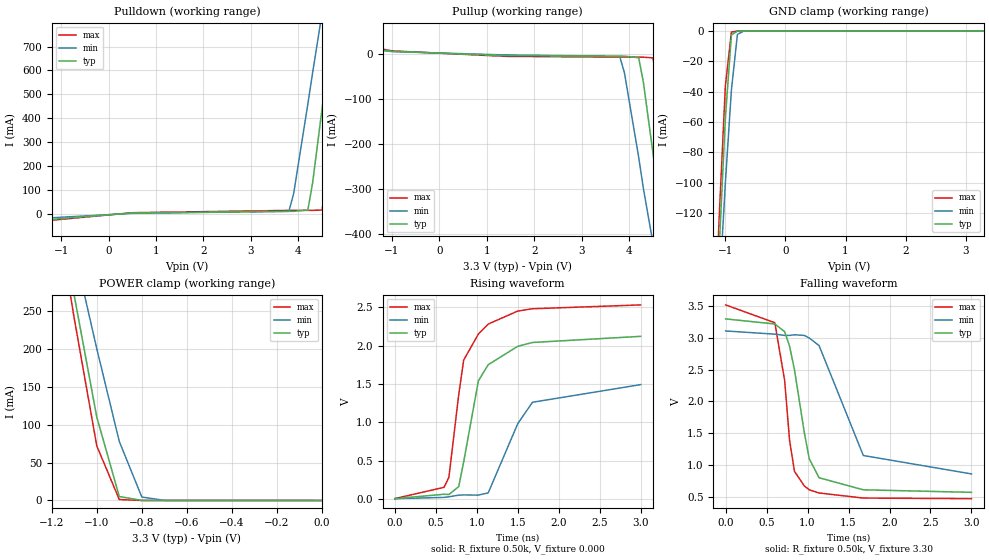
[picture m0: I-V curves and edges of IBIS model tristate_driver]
| IBIS file tristate.ibs created by s2ibis2 version 1.1
| North Carolina State University Electronics Research Laboratory  1995
[IBIS ver]   2.1
[File name]   tristate.ibs
[File Rev]   0
[Date]   April 1, 2001
[Source]   From MegaFLOPS Inc. layout and silicon models.
[Notes]   I really wouldn't try to use this driver. It's really bad.
[Disclaimer]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
[Copyright]   Copyright 2001 MegaFLOPS Inc.
|   Component MCM Trisate Driver
[Component]   MCM Trisate Driver
[Manufacturer]   MegaFLOPS Inc.
[Package]
| variable   typ   min   max
R_pkg   2.00m   1.00m   4.00m
L_pkg   0.20nH   0.10nH   0.40nH
C_pkg   2.00pF   1.00pF   4.00pF
[Pin]  signal_name   model_name   R_pin   L_pin   C_pin
out   out   tristate_driver
| in   in   dummy
| ena  enable   dummy
gnd   gnd   GND
vdd   vdd   POWER
| Models and submodels in the file (1): tristate_driver (3-state)
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|   Model tristate_driver
[Model]   tristate_driver
Model_type   3-state
Polarity   Non-Inverting
Enable   Active-Low
C_comp   5.00pF   5.00pF   5.00pF
[Temperature Range]   27.00   100.00   0.000
[Voltage Range]   3.30V   3.00V   3.60V
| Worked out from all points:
|   slope of the pulldown table from 0 to 0.495 V, typ, clamps not added: 102 ohm
|   slope of the pullup table from 0 to 0.495 V, typ, clamps not added: 229 ohm
|   GND clamp passes 1 mA (typ) near -0.84 V on its own axis
|   POWER clamp passes 1 mA (typ) near -0.82 V on its own axis
|   rising waveform, R_fixture 0.50k, V_fixture 0.000: 20-80 % time 274ps typ, 377ps min, 248ps max; typ from 0.003 V to 2.12 V
|   falling waveform, R_fixture 0.50k, V_fixture 3.30: 20-80 % time 219ps typ, 380ps min, 161ps max; typ from 3.3 V to 0.57 V
[Pulldown]
| voltage   I(typ)   I(min)   I(max)
-3.3V     -51.73mA   -3.31mA    -61.85mA
-2.7V     -45.32mA   -31.67mA   -53.63mA
500mV     4.89mA     3.3mA      5.97mA
3.8V      11.72mA    11.67mA    15.66mA
3.9V      11.73mA    84.95mA    15.68mA
4.2V      17.13mA    460mA      15.72mA
4.3V      130mA      590mA      15.74mA
4.5V      440mA      840mA      17.16mA
4.7V      750mA      1.09A      260mA
4.9V      1.07A      1.35A      610mA
5.1V      1.38A      1.6A       950mA
6.6V      3.74A      3.5A       3.54A
[Pullup]
| voltage   I(typ)   I(min)   I(max)
-3.3V     44.21mA    32.14mA    52.15mA
-1V       5.21mA     4.54mA     6.16mA
1.4V      -4.72mA    -2.92mA    -6.11mA
3.8V      -5.59mA    -5.85mA    -7.73mA
3.9V      -5.62mA    -42.88mA   -7.74mA
4.2V      -9.1mA     -230mA     -7.79mA
4.3V      -64.3mA    -300mA     -7.93mA
4.5V      -220mA     -420mA     -9.41mA
4.7V      -380mA     -550mA     -130mA
4.9V      -540mA     -680mA     -310mA
5.1V      -700mA     -810mA     -480mA
6.6V      -1.89A     -1.77A     -1.79A
[GND_clamp]
| voltage   I(typ)   I(min)   I(max)
-3.3V     -1.88A     -1.57A     -2.04A
-1.2V     -210mA     -230mA     -210mA
-1.1V     -140mA     -170mA     -120mA
-1V       -57.32mA   -100mA     -36.14mA
-900mV    -2.63mA    -39mA      -630uA
-800mV    -55.14uA   -2.27mA    -9.15uA
-700mV    -1.16uA    -100uA     -140nA
3.3V      2.75pA     810pA      2.5pA
[POWER_clamp]
| voltage   I(typ)   I(min)   I(max)
-3.3V     3.73A      3.11A      4.05A
-1.2V     430mA      460mA      420mA
-1.1V     270mA      330mA      240mA
-1V       110mA      200mA      71.98mA
-900mV    5.24mA     77.73mA    1.26mA
-800mV    110uA      4.53mA     17.99uA
-700mV    2.3uA      200uA      260nA
0V        2.75pA     2.68pA     3pA
[Ramp]
| variable   typ   min   max
dV/dt_r   1.27/0.29n   0.89/0.37n   1.52/0.25n
dV/dt_f   1.64/0.20n   1.34/0.33n   1.85/0.16n
R_load = 0.50k
[Rising Waveform]
R_fixture = 0.50k
V_fixture = 0.000
| time   V(typ)   V(min)   V(max)
0s        2.53mV     1.85mV     3.15mV
600ps     59.63mV    18.84mV    150mV
660ps     56.14mV    26.37mV    280mV
780ps     160mV      48.29mV    1.36V
840ps     480mV      50.62mV    1.81V
1.02ns    1.54V      49.2mV     2.15V
1.14ns    1.75V      77.56mV    2.28V
1.5ns     1.99V      980mV      2.45V
1.68ns    2.04V      1.26V      2.48V
3ns       2.12V      1.49V      2.53V
[Falling Waveform]
R_fixture = 0.50k
V_fixture = 3.30
| time   V(typ)   V(min)   V(max)
0s        3.3V       3.11V      3.52V
600ps     3.22V      3.06V      3.24V
720ps     3.1V       3.04V      2.33V
780ps     2.87V      3.04V      1.39V
840ps     2.5V       3.05V      900mV
960ps     1.51V      3.04V      670mV
1.02ns    1.1V       3V         610mV
1.14ns    800mV      2.88V      560mV
1.68ns    610mV      1.15V      480mV
3ns       570mV      860mV      470mV
